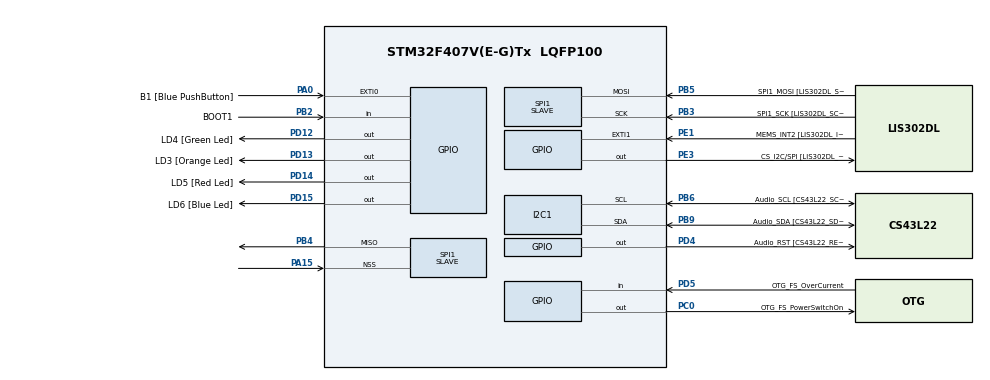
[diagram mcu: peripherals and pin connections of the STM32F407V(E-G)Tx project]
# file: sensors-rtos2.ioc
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Dma.I2C1_RX.0.Direction=DMA_PERIPH_TO_MEMORY
Dma.I2C1_RX.0.FIFOMode=DMA_FIFOMODE_DISABLE
Dma.I2C1_RX.0.Instance=DMA1_Stream0
Dma.I2C1_RX.0.MemDataAlignment=DMA_MDATAALIGN_BYTE
Dma.I2C1_RX.0.MemInc=DMA_MINC_ENABLE
Dma.I2C1_RX.0.Mode=DMA_NORMAL
Dma.I2C1_RX.0.PeriphDataAlignment=DMA_PDATAALIGN_BYTE
Dma.I2C1_RX.0.PeriphInc=DMA_PINC_DISABLE
Dma.I2C1_RX.0.Priority=DMA_PRIORITY_LOW
Dma.I2C1_TX.1.Direction=DMA_MEMORY_TO_PERIPH
Dma.I2C1_TX.1.FIFOMode=DMA_FIFOMODE_DISABLE
Dma.I2C1_TX.1.Instance=DMA1_Stream6
Dma.I2C1_TX.1.MemDataAlignment=DMA_MDATAALIGN_BYTE
Dma.I2C1_TX.1.MemInc=DMA_MINC_ENABLE
Dma.I2C1_TX.1.Mode=DMA_NORMAL
Dma.I2C1_TX.1.PeriphDataAlignment=DMA_PDATAALIGN_BYTE
Dma.I2C1_TX.1.PeriphInc=DMA_PINC_DISABLE
Dma.I2C1_TX.1.Priority=DMA_PRIORITY_LOW
Dma.Request0=I2C1_RX
Dma.Request1=I2C1_TX
Dma.Request2=SPI1_RX
Dma.Request3=SPI1_TX
Dma.SPI1_RX.2.Direction=DMA_PERIPH_TO_MEMORY
Dma.SPI1_RX.2.FIFOMode=DMA_FIFOMODE_DISABLE
Dma.SPI1_RX.2.Instance=DMA2_Stream0
Dma.SPI1_RX.2.MemDataAlignment=DMA_MDATAALIGN_BYTE
Dma.SPI1_RX.2.MemInc=DMA_MINC_ENABLE
Dma.SPI1_RX.2.Mode=DMA_NORMAL
Dma.SPI1_RX.2.PeriphDataAlignment=DMA_PDATAALIGN_BYTE
Dma.SPI1_RX.2.PeriphInc=DMA_PINC_DISABLE
Dma.SPI1_RX.2.Priority=DMA_PRIORITY_LOW
Dma.SPI1_TX.3.Direction=DMA_MEMORY_TO_PERIPH
Dma.SPI1_TX.3.FIFOMode=DMA_FIFOMODE_DISABLE
Dma.SPI1_TX.3.Instance=DMA2_Stream3
Dma.SPI1_TX.3.MemDataAlignment=DMA_MDATAALIGN_BYTE
Dma.SPI1_TX.3.MemInc=DMA_MINC_ENABLE
Dma.SPI1_TX.3.Mode=DMA_NORMAL
Dma.SPI1_TX.3.PeriphDataAlignment=DMA_PDATAALIGN_BYTE
Dma.SPI1_TX.3.PeriphInc=DMA_PINC_DISABLE
Dma.SPI1_TX.3.Priority=DMA_PRIORITY_LOW
FREERTOS.Tasks01=defaultTask,0,128,StartDefaultTask,Default,NULL,Dynamic,NULL,NULL;AccGyroTask,1,128,AccGyroTaskEntry,As external,NULL,Dynamic,NULL,NULL;MagTask,1,128,MagTaskEntry,As external,NULL,Dynamic,NULL,NULL;DebugLEDTask,0,128,DebugLEDTaskEntry,As external,NULL,Dynamic,NULL,NULL;AHRSUpdate,1,128,AHRSUpdateTaskEntry,As external,NULL,Dynamic,NULL,NULL;SPITask,1,128,SPITaskEntry,As external,NULL,Dynamic,NULL,NULL
FREERTOS.configUSE_TIMERS=1
I2C1.I2C_Mode=I2C_Fast
Mcu.Family=STM32F4
Mcu.Name=STM32F407V(E-G)Tx
Mcu.Package=LQFP100
NVIC.DMA1_Stream0_IRQn=true\:0\:0\:false\:false\:true\:false\:false
NVIC.DMA1_Stream6_IRQn=true\:0\:0\:false\:false\:true\:false\:false
NVIC.DMA2_Stream0_IRQn=true\:5\:0\:false\:true\:true\:1\:true\:false
NVIC.DMA2_Stream3_IRQn=true\:5\:0\:false\:true\:true\:2\:true\:false
NVIC.I2C1_ER_IRQn=true\:0\:0\:false\:true\:true\:5\:false\:true
NVIC.I2C1_EV_IRQn=true\:0\:0\:false\:true\:true\:4\:false\:true
NVIC.PriorityGroup=NVIC_PRIORITYGROUP_4
NVIC.SPI1_IRQn=true\:5\:0\:false\:true\:true\:3\:true\:true
NVIC.TIM3_IRQn=true\:0\:0\:false\:false\:true\:false\:false
NVIC.TimeBase=TIM3_IRQn
NVIC.TimeBaseIP=TIM3
PA0-WKUP.GPIO_Label=B1 [Blue PushButton]
PA0-WKUP.Signal=GPXTI0
PA10.GPIO_Label=OTG_FS_ID
PA10.GPIO_Mode=GPIO_MODE_AF_PP
PA10.GPIO_PuPd=GPIO_NOPULL
PA10.GPIO_Speed=GPIO_SPEED_FREQ_LOW
PA10.Signal=USB_OTG_FS_ID
PA11.GPIO_Label=OTG_FS_DM
PA11.GPIO_Mode=GPIO_MODE_AF_PP
PA11.GPIO_PuPd=GPIO_NOPULL
PA11.GPIO_Speed=GPIO_SPEED_FREQ_LOW
PA11.Signal=USB_OTG_FS_DM
PA12.GPIO_Label=OTG_FS_DP
PA12.GPIO_Mode=GPIO_MODE_AF_PP
PA12.GPIO_PuPd=GPIO_NOPULL
PA12.GPIO_Speed=GPIO_SPEED_FREQ_LOW
PA12.Signal=USB_OTG_FS_DP
PA13.GPIO_Label=SWDIO
PA13.Signal=SYS_JTMS-SWDIO
PA14.GPIO_Label=SWCLK
PA14.Signal=SYS_JTCK-SWCLK
PA15.Mode=NSS_Signal_Hard_Input
PA15.Signal=SPI1_NSS
PA4.GPIO_Label=I2S3_WS [CS43L22_LRCK]
PA4.GPIO_Mode=GPIO_MODE_AF_PP
PA4.GPIO_PuPd=GPIO_NOPULL
PA4.GPIO_Speed=GPIO_SPEED_FREQ_LOW
PA4.Signal=I2S3_WS
PA9.GPIO_Label=VBUS_FS
PA9.GPIO_Mode=GPIO_MODE_INPUT
PA9.GPIO_PuPd=GPIO_NOPULL
PA9.Signal=USB_OTG_FS_VBUS
PB10.GPIO_Label=CLK_IN [MP45DT02_CLK]
PB10.GPIO_Mode=GPIO_MODE_AF_PP
PB10.GPIO_PuPd=GPIO_NOPULL
PB10.GPIO_Speed=GPIO_SPEED_FREQ_LOW
PB10.Signal=I2S2_CK
PB2.GPIO_Label=BOOT1
PB2.GPIO_Mode=GPIO_MODE_INPUT
PB2.GPIO_PuPd=GPIO_NOPULL
PB2.Signal=GPIO_Input
PB3.GPIO_Label=SPI1_SCK [LIS302DL_SCL/SPC]
PB3.GPIO_Mode=GPIO_MODE_AF_PP
PB3.GPIO_PuPd=GPIO_NOPULL
PB3.GPIO_Speed=GPIO_SPEED_FREQ_HIGH
PB3.Mode=Full_Duplex_Slave
PB3.Signal=SPI1_SCK
PB4.Mode=Full_Duplex_Slave
PB4.Signal=SPI1_MISO
PB5.GPIO_Label=SPI1_MOSI [LIS302DL_SDA/SDI/SDO]
PB5.GPIO_Mode=GPIO_MODE_AF_PP
PB5.GPIO_PuPd=GPIO_NOPULL
PB5.GPIO_Speed=GPIO_SPEED_FREQ_HIGH
PB5.Mode=Full_Duplex_Slave
PB5.Signal=SPI1_MOSI
PB6.GPIO_Label=Audio_SCL [CS43L22_SCL]
PB6.GPIO_Mode=GPIO_MODE_AF_OD
PB6.GPIO_PuPd=GPIO_NOPULL
PB6.GPIO_Speed=GPIO_SPEED_FREQ_HIGH
PB6.Mode=I2C
PB6.Signal=I2C1_SCL
PB9.GPIO_Label=Audio_SDA [CS43L22_SDA]
PB9.GPIO_Mode=GPIO_MODE_AF_OD
PB9.GPIO_PuPd=GPIO_NOPULL
PB9.GPIO_Speed=GPIO_SPEED_FREQ_HIGH
PB9.Mode=I2C
PB9.Signal=I2C1_SDA
PC0.GPIO_Label=OTG_FS_PowerSwitchOn
PC0.GPIO_PuPd=GPIO_NOPULL
PC0.GPIO_Speed=GPIO_SPEED_FREQ_LOW
PC0.PinState=GPIO_PIN_SET
PC0.Signal=GPIO_Output
PC10.GPIO_Label=I2S3_SCK [CS43L22_SCLK]
PC10.GPIO_Mode=GPIO_MODE_AF_PP
PC10.GPIO_PuPd=GPIO_NOPULL
PC10.GPIO_Speed=GPIO_SPEED_FREQ_LOW
PC10.Signal=I2S3_CK
PC12.GPIO_Label=I2S3_SD [CS43L22_SDIN]
PC12.GPIO_Mode=GPIO_MODE_AF_PP
PC12.GPIO_PuPd=GPIO_NOPULL
PC12.GPIO_Speed=GPIO_SPEED_FREQ_LOW
PC12.Signal=I2S3_SD
PC14-OSC32_IN.GPIO_Label=PC14-OSC32_IN
PC14-OSC32_IN.Signal=RCC_OSC32_IN
PC15-OSC32_OUT.GPIO_Label=PC15-OSC32_OUT
PC15-OSC32_OUT.Signal=RCC_OSC32_OUT
PC3.GPIO_Label=PDM_OUT [MP45DT02_DOUT]
PC3.GPIO_Mode=GPIO_MODE_AF_PP
PC3.GPIO_PuPd=GPIO_NOPULL
PC3.GPIO_Speed=GPIO_SPEED_FREQ_LOW
PC3.Signal=I2S2_SD
PC7.GPIO_Label=I2S3_MCK [CS43L22_MCLK]
PC7.GPIO_Mode=GPIO_MODE_AF_PP
PC7.GPIO_PuPd=GPIO_NOPULL
PC7.GPIO_Speed=GPIO_SPEED_FREQ_LOW
PC7.Signal=I2S3_MCK
PD12.GPIO_Label=LD4 [Green Led]
PD12.GPIO_PuPd=GPIO_NOPULL
PD12.GPIO_Speed=GPIO_SPEED_FREQ_LOW
PD12.Signal=GPIO_Output
PD13.GPIO_Label=LD3 [Orange Led]
PD13.GPIO_PuPd=GPIO_NOPULL
PD13.GPIO_Speed=GPIO_SPEED_FREQ_LOW
PD13.Signal=GPIO_Output
PD14.GPIO_Label=LD5 [Red Led]
PD14.GPIO_PuPd=GPIO_NOPULL
PD14.GPIO_Speed=GPIO_SPEED_FREQ_LOW
PD14.Signal=GPIO_Output
PD15.GPIO_Label=LD6 [Blue Led]
PD15.GPIO_PuPd=GPIO_NOPULL
PD15.GPIO_Speed=GPIO_SPEED_FREQ_LOW
PD15.Signal=GPIO_Output
PD4.GPIO_Label=Audio_RST [CS43L22_RESET]
PD4.GPIO_PuPd=GPIO_NOPULL
PD4.GPIO_Speed=GPIO_SPEED_FREQ_LOW
PD4.Signal=GPIO_Output
PD5.GPIO_Label=OTG_FS_OverCurrent
PD5.GPIO_Mode=GPIO_MODE_INPUT
PD5.GPIO_PuPd=GPIO_NOPULL
PD5.Signal=GPIO_Input
PE1.GPIO_Label=MEMS_INT2 [LIS302DL_INT2]
PE1.GPIO_ModeDefaultEXTI=GPIO_MODE_EVT_RISING
PE1.GPIO_PuPd=GPIO_NOPULL
PE1.Signal=GPXTI1
PE3.GPIO_Label=CS_I2C/SPI [LIS302DL_CS_I2C/SPI]
PE3.GPIO_PuPd=GPIO_NOPULL
PE3.GPIO_Speed=GPIO_SPEED_FREQ_LOW
PE3.Signal=GPIO_Output
PH0-OSC_IN.GPIO_Label=PH0-OSC_IN
PH0-OSC_IN.Signal=RCC_OSC_IN
PH1-OSC_OUT.GPIO_Label=PH1-OSC_OUT
PH1-OSC_OUT.Signal=RCC_OSC_OUT
ProjectManager.HeapSize=0x200
ProjectManager.StackSize=0x400
ProjectManager.TargetToolchain=SW4STM32
RCC.48MHZClocksFreq_Value=48000000
RCC.AHBFreq_Value=168000000
RCC.APB1CLKDivider=RCC_HCLK_DIV4
RCC.APB1Freq_Value=42000000
RCC.APB1TimFreq_Value=84000000
RCC.APB2CLKDivider=RCC_HCLK_DIV2
RCC.APB2Freq_Value=84000000
RCC.APB2TimFreq_Value=168000000
RCC.CortexFreq_Value=168000000
RCC.HCLKFreq_Value=168000000
RCC.HSE_VALUE=8000000
RCC.HSI_VALUE=16000000
RCC.LSE_VALUE=32768
RCC.PLLM=8
RCC.PLLN=168
RCC.PLLQ=7
RCC.SYSCLKFreq_VALUE=168000000
RCC.SYSCLKSource=RCC_SYSCLKSOURCE_PLLCLK
RCC.VCOOutputFreq_Value=336000000
SPI1.DataSize=SPI_DATASIZE_8BIT
SPI1.Direction=SPI_DIRECTION_2LINES
SPI1.Mode=SPI_MODE_SLAVE
SPI1.VirtualNSS=VM_NSSHARD
SPI1.VirtualType=VM_SLAVE
VP_FREERTOS_VS_ENABLE.Mode=Enabled
VP_IWDG_VS_IWDG.Mode=IWDG_Activate
VP_SYS_VS_tim3.Mode=TIM3
board=STM32F4DISCOVERY

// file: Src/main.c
/**
  ******************************************************************************
  * @file           : main.c
  * @brief          : Main program body
  ******************************************************************************
  * This notice applies to any and all portions of this file
  * that are not between comment pairs USER CODE BEGIN and
  * USER CODE END. Other portions of this file, whether
  * inserted by the user or by software development tools
  * are owned by their respective copyright owners.
  *
  * Copyright (c) 2018 STMicroelectronics International N.V.
  * All rights reserved.
  *
  * Redistribution and use in source and binary forms, with or without
  * modification, are permitted, provided that the following conditions are met:
  *
  * 1. Redistribution of source code must retain the above copyright notice,
  *    this list of conditions and the following disclaimer.
  * 2. Redistributions in binary form must reproduce the above copyright notice,
  *    this list of conditions and the following disclaimer in the documentation
  *    and/or other materials provided with the distribution.
  * 3. Neither the name of STMicroelectronics nor the names of other
  *    contributors to this software may be used to endorse or promote products
  *    derived from this software without specific written permission.
  * 4. This software, including modifications and/or derivative works of this
  *    software, must execute solely and exclusively on microcontroller or
  *    microprocessor devices manufactured by or for STMicroelectronics.
  * 5. Redistribution and use of this software other than as permitted under
  *    this license is void and will automatically terminate your rights under
  *    this license.
  *
  * THIS SOFTWARE IS PROVIDED BY STMICROELECTRONICS AND CONTRIBUTORS "AS IS"
  * AND ANY EXPRESS, IMPLIED OR STATUTORY WARRANTIES, INCLUDING, BUT NOT
  * LIMITED TO, THE IMPLIED WARRANTIES OF MERCHANTABILITY, FITNESS FOR A
  * PARTICULAR PURPOSE AND NON-INFRINGEMENT OF THIRD PARTY INTELLECTUAL PROPERTY
  * RIGHTS ARE DISCLAIMED TO THE FULLEST EXTENT PERMITTED BY LAW. IN NO EVENT
  * SHALL STMICROELECTRONICS OR CONTRIBUTORS BE LIABLE FOR ANY DIRECT, INDIRECT,
  * INCIDENTAL, SPECIAL, EXEMPLARY, OR CONSEQUENTIAL DAMAGES (INCLUDING, BUT NOT
  * LIMITED TO, PROCUREMENT OF SUBSTITUTE GOODS OR SERVICES; LOSS OF USE, DATA,
  * OR PROFITS; OR BUSINESS INTERRUPTION) HOWEVER CAUSED AND ON ANY THEORY OF
  * LIABILITY, WHETHER IN CONTRACT, STRICT LIABILITY, OR TORT (INCLUDING
  * NEGLIGENCE OR OTHERWISE) ARISING IN ANY WAY OUT OF THE USE OF THIS SOFTWARE,
  * EVEN IF ADVISED OF THE POSSIBILITY OF SUCH DAMAGE.
  *
  ******************************************************************************
  */
#include "main.h"
#include "stm32f4xx_hal.h"
#include "cmsis_os.h"
#include "dma.h"
#include "i2c.h"
#include "iwdg.h"
#include "spi.h"
#include "gpio.h"

/* USER CODE BEGIN Includes */
#include "sensors.h"
#include "tasks.h"
#include "eeprom.h"
/* USER CODE END Includes */

/* USER CODE BEGIN PV */
/* Private variables ---------------------------------------------------------*/

/* USER CODE END PV */

void SystemClock_Config(void);
void MX_FREERTOS_Init(void);
static void MX_NVIC_Init(void);

/* USER CODE BEGIN PFP */
/* Private function prototypes -----------------------------------------------*/

/* USER CODE END PFP */

/* USER CODE BEGIN 0 */
uint16_t VirtAddVarTab[NB_OF_VAR] = {0x0000, 0x0001, 0x0002,0x0003};

/* USER CODE END 0 */

int main(void)
{

  /* MCU Configuration----------------------------------------------------------*/

  /* Reset of all peripherals, Initializes the Flash interface and the Systick. */
  HAL_Init();

  /* USER CODE BEGIN Init */
  HAL_FLASH_Unlock();

  /* USER CODE END Init */

  /* Configure the system clock */
  SystemClock_Config();

  /* USER CODE BEGIN SysInit */
  if(__HAL_RCC_GET_FLAG(RCC_FLAG_IWDGRST) != RESET)
   {
     /* IWDGRST flag set: Turn LED1 on */
	  HAL_GPIO_TogglePin(GPIOD,GPIO_PIN_14);

     /* Clear reset flags */
     __HAL_RCC_CLEAR_RESET_FLAGS();
   }
  /* USER CODE END SysInit */

  /* Initialize all configured peripherals */
  MX_GPIO_Init();
  MX_DMA_Init();
  MX_SPI1_Init();
  MX_I2C1_Init();

  /* Initialize interrupts */
  MX_NVIC_Init();
  /* USER CODE BEGIN 2 */
  EE_Init();
  SensorsInit();

  /* USER CODE END 2 */

  /* Call init function for freertos objects (in freertos.c) */
  MX_FREERTOS_Init();
	MX_IWDG_Init();

  /* Start scheduler */
  osKernelStart();

  /* We should never get here as control is now taken by the scheduler */

  /* Infinite loop */
  while (1)
  {

  }

}

void SystemClock_Config(void)
{

  RCC_OscInitTypeDef RCC_OscInitStruct;
  RCC_ClkInitTypeDef RCC_ClkInitStruct;

    /**Configure the main internal regulator output voltage
    */
  __HAL_RCC_PWR_CLK_ENABLE();

  __HAL_PWR_VOLTAGESCALING_CONFIG(PWR_REGULATOR_VOLTAGE_SCALE1);

    /**Initializes the CPU, AHB and APB busses clocks
    */
  RCC_OscInitStruct.OscillatorType = RCC_OSCILLATORTYPE_HSI|RCC_OSCILLATORTYPE_LSI;
  RCC_OscInitStruct.HSIState = RCC_HSI_ON;
  RCC_OscInitStruct.HSICalibrationValue = 16;
  RCC_OscInitStruct.LSIState = RCC_LSI_ON;
  RCC_OscInitStruct.PLL.PLLState = RCC_PLL_ON;
  RCC_OscInitStruct.PLL.PLLSource = RCC_PLLSOURCE_HSI;
  RCC_OscInitStruct.PLL.PLLM = 8;
  RCC_OscInitStruct.PLL.PLLN = 50;
  RCC_OscInitStruct.PLL.PLLP = RCC_PLLP_DIV2;
  RCC_OscInitStruct.PLL.PLLQ = 7;
  if (HAL_RCC_OscConfig(&RCC_OscInitStruct) != HAL_OK)
  {
    _Error_Handler(__FILE__, __LINE__);
  }

    /**Initializes the CPU, AHB and APB busses clocks
    */
  RCC_ClkInitStruct.ClockType = RCC_CLOCKTYPE_HCLK|RCC_CLOCKTYPE_SYSCLK
                              |RCC_CLOCKTYPE_PCLK1|RCC_CLOCKTYPE_PCLK2;
  RCC_ClkInitStruct.SYSCLKSource = RCC_SYSCLKSOURCE_PLLCLK;
  RCC_ClkInitStruct.AHBCLKDivider = RCC_SYSCLK_DIV2;
  RCC_ClkInitStruct.APB1CLKDivider = RCC_HCLK_DIV4;
  RCC_ClkInitStruct.APB2CLKDivider = RCC_HCLK_DIV2;

  if (HAL_RCC_ClockConfig(&RCC_ClkInitStruct, FLASH_LATENCY_0) != HAL_OK)
  {
    _Error_Handler(__FILE__, __LINE__);
  }

    /**Configure the Systick interrupt time
    */
  HAL_SYSTICK_Config(HAL_RCC_GetHCLKFreq()/1000);

    /**Configure the Systick
    */
  HAL_SYSTICK_CLKSourceConfig(SYSTICK_CLKSOURCE_HCLK);

  /* SysTick_IRQn interrupt configuration */
  HAL_NVIC_SetPriority(SysTick_IRQn, 15, 0);
}

/**
  * @brief NVIC Configuration.
  * @retval None
  */
static void MX_NVIC_Init(void)
{
  /* I2C1_EV_IRQn interrupt configuration */
  HAL_NVIC_SetPriority(I2C1_EV_IRQn, 0, 0);
  HAL_NVIC_EnableIRQ(I2C1_EV_IRQn);
  /* I2C1_ER_IRQn interrupt configuration */
  HAL_NVIC_SetPriority(I2C1_ER_IRQn, 0, 0);
  HAL_NVIC_EnableIRQ(I2C1_ER_IRQn);
}

void HAL_TIM_PeriodElapsedCallback(TIM_HandleTypeDef *htim)
{
  if (htim->Instance == TIM3) {
    HAL_IncTick();
  }
}

void _Error_Handler(char *file, int line)
{
  while(1)
  {
  }
}

/************************ (C) COPYRIGHT STMicroelectronics *****END OF FILE****/

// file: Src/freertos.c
/**
  ******************************************************************************
  * File Name          : freertos.c
  * Description        : Code for freertos applications
  ******************************************************************************
  * This notice applies to any and all portions of this file
  * that are not between comment pairs USER CODE BEGIN and
  * USER CODE END. Other portions of this file, whether
  * inserted by the user or by software development tools
  * are owned by their respective copyright owners.
  *
  * Copyright (c) 2018 STMicroelectronics International N.V.
  * All rights reserved.
  *
  * Redistribution and use in source and binary forms, with or without
  * modification, are permitted, provided that the following conditions are met:
  *
  * 1. Redistribution of source code must retain the above copyright notice,
  *    this list of conditions and the following disclaimer.
  * 2. Redistributions in binary form must reproduce the above copyright notice,
  *    this list of conditions and the following disclaimer in the documentation
  *    and/or other materials provided with the distribution.
  * 3. Neither the name of STMicroelectronics nor the names of other
  *    contributors to this software may be used to endorse or promote products
  *    derived from this software without specific written permission.
  * 4. This software, including modifications and/or derivative works of this
  *    software, must execute solely and exclusively on microcontroller or
  *    microprocessor devices manufactured by or for STMicroelectronics.
  * 5. Redistribution and use of this software other than as permitted under
  *    this license is void and will automatically terminate your rights under
  *    this license.
  *
  * THIS SOFTWARE IS PROVIDED BY STMICROELECTRONICS AND CONTRIBUTORS "AS IS"
  * AND ANY EXPRESS, IMPLIED OR STATUTORY WARRANTIES, INCLUDING, BUT NOT
  * LIMITED TO, THE IMPLIED WARRANTIES OF MERCHANTABILITY, FITNESS FOR A
  * PARTICULAR PURPOSE AND NON-INFRINGEMENT OF THIRD PARTY INTELLECTUAL PROPERTY
  * RIGHTS ARE DISCLAIMED TO THE FULLEST EXTENT PERMITTED BY LAW. IN NO EVENT
  * SHALL STMICROELECTRONICS OR CONTRIBUTORS BE LIABLE FOR ANY DIRECT, INDIRECT,
  * INCIDENTAL, SPECIAL, EXEMPLARY, OR CONSEQUENTIAL DAMAGES (INCLUDING, BUT NOT
  * LIMITED TO, PROCUREMENT OF SUBSTITUTE GOODS OR SERVICES; LOSS OF USE, DATA,
  * OR PROFITS; OR BUSINESS INTERRUPTION) HOWEVER CAUSED AND ON ANY THEORY OF
  * LIABILITY, WHETHER IN CONTRACT, STRICT LIABILITY, OR TORT (INCLUDING
  * NEGLIGENCE OR OTHERWISE) ARISING IN ANY WAY OUT OF THE USE OF THIS SOFTWARE,
  * EVEN IF ADVISED OF THE POSSIBILITY OF SUCH DAMAGE.
  *
  ******************************************************************************
  */

#include "FreeRTOS.h"
#include "task.h"
#include "cmsis_os.h"

osThreadId defaultTaskHandle;
osThreadId AccGyroTaskHandle;
osThreadId MagTaskHandle;
osThreadId DebugLEDTaskHandle;
osThreadId AHRSUpdateHandle;
osThreadId SPITaskHandle;

void StartDefaultTask(void const * argument);
extern void AccGyroTaskEntry(void const * argument);
extern void MagTaskEntry(void const * argument);
extern void DebugLEDTaskEntry(void const * argument);
extern void AHRSUpdateTaskEntry(void const * argument);
extern void SPITaskEntry(void const * argument);

void MX_FREERTOS_Init(void); /* (MISRA C 2004 rule 8.1) */

/* Hook prototypes */

/* Init FreeRTOS */

void MX_FREERTOS_Init(void) {

  /* Create the thread(s) */
  /* definition and creation of defaultTask */
  osThreadDef(defaultTask, StartDefaultTask, osPriorityNormal, 0, 128);
  defaultTaskHandle = osThreadCreate(osThread(defaultTask), NULL);

  /* definition and creation of AccGyroTask */
  osThreadDef(AccGyroTask, AccGyroTaskEntry, osPriorityAboveNormal, 0, 128);
  AccGyroTaskHandle = osThreadCreate(osThread(AccGyroTask), NULL);

  /* definition and creation of MagTask */
  osThreadDef(MagTask, MagTaskEntry, osPriorityAboveNormal, 0, 128);
  MagTaskHandle = osThreadCreate(osThread(MagTask), NULL);

  /* definition and creation of DebugLEDTask */
  osThreadDef(DebugLEDTask, DebugLEDTaskEntry, osPriorityNormal, 0, 128);
  DebugLEDTaskHandle = osThreadCreate(osThread(DebugLEDTask), NULL);

  /* definition and creation of AHRSUpdate */
  osThreadDef(AHRSUpdate, AHRSUpdateTaskEntry, osPriorityAboveNormal, 0, 128);
  AHRSUpdateHandle = osThreadCreate(osThread(AHRSUpdate), NULL);

  /* definition and creation of SPITask */
  osThreadDef(SPITask, SPITaskEntry, osPriorityAboveNormal, 0, 128);
  SPITaskHandle = osThreadCreate(osThread(SPITask), NULL);

}

/* StartDefaultTask function */
void StartDefaultTask(void const * argument)
{

  for(;;)
  {
    osDelay(1);
  }
}

/************************ (C) COPYRIGHT STMicroelectronics *****END OF FILE****/
